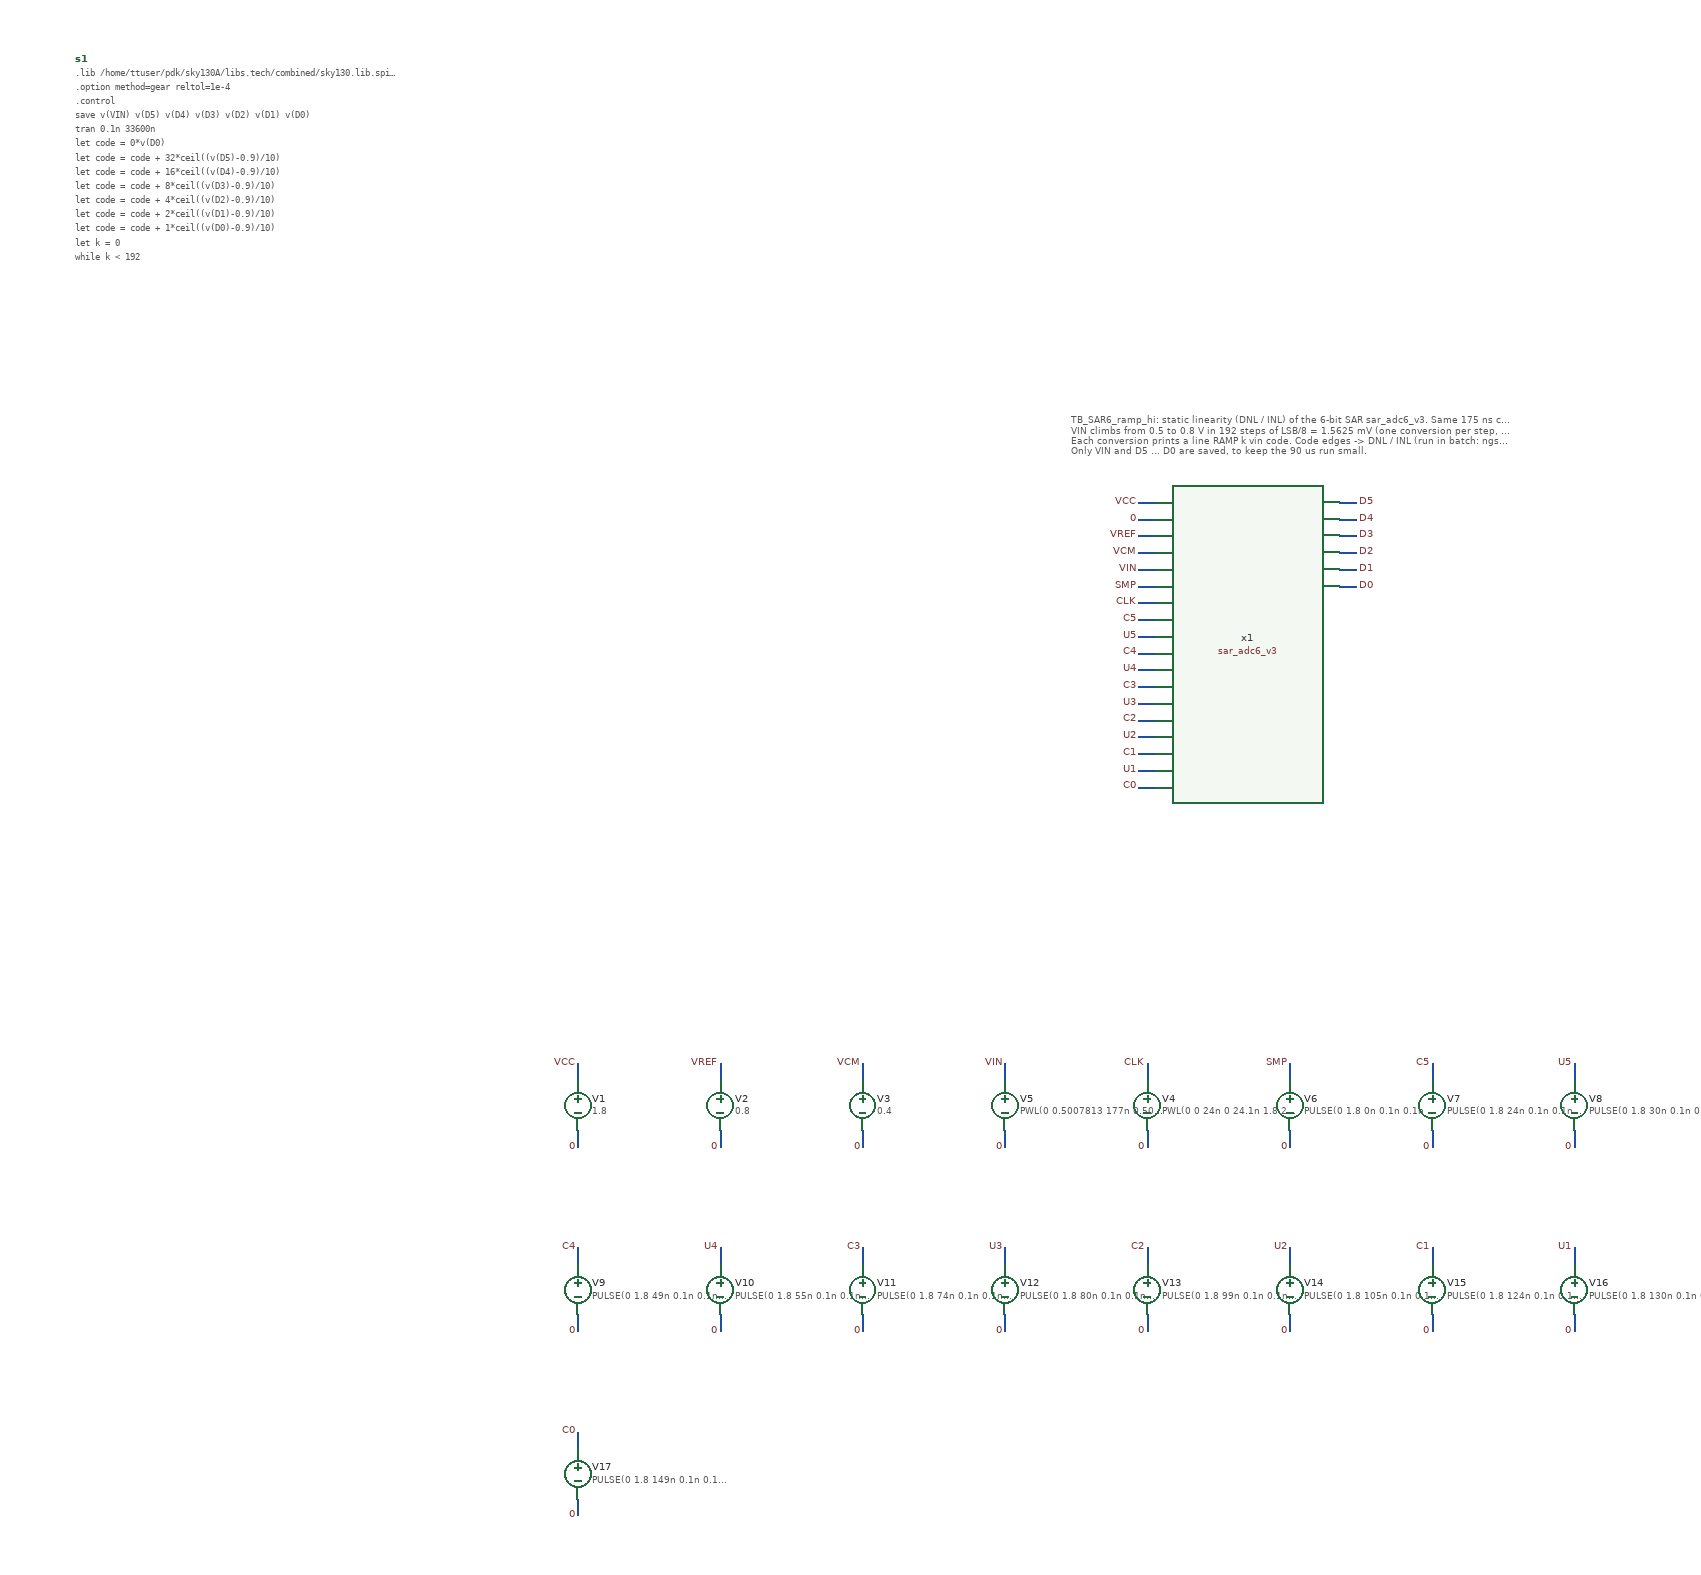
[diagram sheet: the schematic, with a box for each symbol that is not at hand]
v {xschem version=3.4.5 file_version=1.2
}
G {}
K {}
V {}
S {}
E {}
T {TB_SAR6_ramp_hi: static linearity (DNL / INL) of the 6-bit SAR sar_adc6_v3.  Same 175 ns conversion timing as TB_SAR6_v3.
VIN climbs from 0.5 to 0.8 V in 192 steps of LSB/8 = 1.5625 mV (one conversion per step, VIN changes 2 ns into SMP).
Each conversion prints a line  RAMP k vin code.  Code edges -> DNL / INL (run in batch:  ngspice -b TB_SAR6_ramp.spice > ramp_log.txt).
Only VIN and D5 ... D0 are saved, to keep the 90 us run small.} 290 -630 0 0 0.3 0.3 {}
C {/home/ttuser/Documents/ADCAnalogDesign/SAR_improved/sar_adc6_v3.sym} 500 -350 0 0 {name=x1}
N 390 -520 370 -520 {}
C {lab_pin.sym} 370 -520 0 0 {name=l1 sig_type=std_logic lab=VCC}
N 390 -500 370 -500 {}
C {lab_pin.sym} 370 -500 0 0 {name=l2 sig_type=std_logic lab=0}
N 390 -480 370 -480 {}
C {lab_pin.sym} 370 -480 0 0 {name=l3 sig_type=std_logic lab=VREF}
N 390 -460 370 -460 {}
C {lab_pin.sym} 370 -460 0 0 {name=l4 sig_type=std_logic lab=VCM}
N 390 -440 370 -440 {}
C {lab_pin.sym} 370 -440 0 0 {name=l5 sig_type=std_logic lab=VIN}
N 390 -420 370 -420 {}
C {lab_pin.sym} 370 -420 0 0 {name=l6 sig_type=std_logic lab=SMP}
N 390 -400 370 -400 {}
C {lab_pin.sym} 370 -400 0 0 {name=l7 sig_type=std_logic lab=CLK}
N 390 -380 370 -380 {}
C {lab_pin.sym} 370 -380 0 0 {name=l8 sig_type=std_logic lab=C5}
N 390 -360 370 -360 {}
C {lab_pin.sym} 370 -360 0 0 {name=l9 sig_type=std_logic lab=U5}
N 390 -340 370 -340 {}
C {lab_pin.sym} 370 -340 0 0 {name=l10 sig_type=std_logic lab=C4}
N 390 -320 370 -320 {}
C {lab_pin.sym} 370 -320 0 0 {name=l11 sig_type=std_logic lab=U4}
N 390 -300 370 -300 {}
C {lab_pin.sym} 370 -300 0 0 {name=l12 sig_type=std_logic lab=C3}
N 390 -280 370 -280 {}
C {lab_pin.sym} 370 -280 0 0 {name=l13 sig_type=std_logic lab=U3}
N 390 -260 370 -260 {}
C {lab_pin.sym} 370 -260 0 0 {name=l14 sig_type=std_logic lab=C2}
N 390 -240 370 -240 {}
C {lab_pin.sym} 370 -240 0 0 {name=l15 sig_type=std_logic lab=U2}
N 390 -220 370 -220 {}
C {lab_pin.sym} 370 -220 0 0 {name=l16 sig_type=std_logic lab=C1}
N 390 -200 370 -200 {}
C {lab_pin.sym} 370 -200 0 0 {name=l17 sig_type=std_logic lab=U1}
N 390 -180 370 -180 {}
C {lab_pin.sym} 370 -180 0 0 {name=l18 sig_type=std_logic lab=C0}
N 610 -520 630 -520 {}
C {lab_pin.sym} 630 -520 0 1 {name=l19 sig_type=std_logic lab=D5}
N 610 -500 630 -500 {}
C {lab_pin.sym} 630 -500 0 1 {name=l20 sig_type=std_logic lab=D4}
N 610 -480 630 -480 {}
C {lab_pin.sym} 630 -480 0 1 {name=l21 sig_type=std_logic lab=D3}
N 610 -460 630 -460 {}
C {lab_pin.sym} 630 -460 0 1 {name=l22 sig_type=std_logic lab=D2}
N 610 -440 630 -440 {}
C {lab_pin.sym} 630 -440 0 1 {name=l23 sig_type=std_logic lab=D1}
N 610 -420 630 -420 {}
C {lab_pin.sym} 630 -420 0 1 {name=l24 sig_type=std_logic lab=D0}
C {vsource.sym} -300 200 0 0 {name=V1 value="1.8" savecurrent=false}
N -300 170 -300 150 {}
C {lab_pin.sym} -300 150 0 0 {name=l25 sig_type=std_logic lab=VCC}
N -300 230 -300 250 {}
C {lab_pin.sym} -300 250 0 0 {name=l26 sig_type=std_logic lab=0}
C {vsource.sym} -130 200 0 0 {name=V2 value="0.8" savecurrent=false}
N -130 170 -130 150 {}
C {lab_pin.sym} -130 150 0 0 {name=l27 sig_type=std_logic lab=VREF}
N -130 230 -130 250 {}
C {lab_pin.sym} -130 250 0 0 {name=l28 sig_type=std_logic lab=0}
C {vsource.sym} 40 200 0 0 {name=V3 value="0.4" savecurrent=false}
N 40 170 40 150 {}
C {lab_pin.sym} 40 150 0 0 {name=l29 sig_type=std_logic lab=VCM}
N 40 230 40 250 {}
C {lab_pin.sym} 40 250 0 0 {name=l30 sig_type=std_logic lab=0}
C {vsource.sym} 210 200 0 0 {name=V5 value="PWL(0 0.5007813 177n 0.5007813 177.5n 0.5023437 352n 0.5023437 352.5n 0.5039062 527n 0.5039062 527.5n 0.5054688 702n 0.5054688 702.5n 0.5070313 877n 0.5070313 877.5n 0.5085938 1052n 0.5085938 1052.5n 0.5101562 1227n 0.5101562 1227.5n 0.5117188 1402n 0.5117188 1402.5n 0.5132813 1577n 0.5132813 1577.5n 0.5148438 1752n 0.5148438 1752.5n 0.5164063 1927n 0.5164063 1927.5n 0.5179687 2102n 0.5179687 2102.5n 0.5195312 2277n 0.5195312 2277.5n 0.5210938 2452n 0.5210938 2452.5n 0.5226563 2627n 0.5226563 2627.5n 0.5242188 2802n 0.5242188 2802.5n 0.5257812 2977n 0.5257812 2977.5n 0.5273438 3152n 0.5273438 3152.5n 0.5289063 3327n 0.5289063 3327.5n 0.5304688 3502n 0.5304688 3502.5n 0.5320313 3677n 0.5320313 3677.5n 0.5335937 3852n 0.5335937 3852.5n 0.5351562 4027n 0.5351562 4027.5n 0.5367188 4202n 0.5367188 4202.5n 0.5382813 4377n 0.5382813 4377.5n 0.5398438 4552n 0.5398438 4552.5n 0.5414062 4727n 0.5414062 4727.5n 0.5429688 4902n 0.5429688 4902.5n 0.5445313 5077n 0.5445313 5077.5n 0.5460938 5252n 0.5460938 5252.5n 0.5476563 5427n 0.5476563 5427.5n 0.5492187 5602n 0.5492187 5602.5n 0.5507812 5777n 0.5507812 5777.5n 0.5523438 5952n 0.5523438 5952.5n 0.5539063 6127n 0.5539063 6127.5n 0.5554688 6302n 0.5554688 6302.5n 0.5570312 6477n 0.5570312 6477.5n 0.5585938 6652n 0.5585938 6652.5n 0.5601563 6827n 0.5601563 6827.5n 0.5617188 7002n 0.5617188 7002.5n 0.5632813 7177n 0.5632813 7177.5n 0.5648437 7352n 0.5648437 7352.5n 0.5664062 7527n 0.5664062 7527.5n 0.5679688 7702n 0.5679688 7702.5n 0.5695313 7877n 0.5695313 7877.5n 0.5710938 8052n 0.5710938 8052.5n 0.5726562 8227n 0.5726562 8227.5n 0.5742188 8402n 0.5742188 8402.5n 0.5757813 8577n 0.5757813 8577.5n 0.5773438 8752n 0.5773438 8752.5n 0.5789063 8927n 0.5789063 8927.5n 0.5804687 9102n 0.5804687 9102.5n 0.5820312 9277n 0.5820312 9277.5n 0.5835938 9452n 0.5835938 9452.5n 0.5851563 9627n 0.5851563 9627.5n 0.5867188 9802n 0.5867188 9802.5n 0.5882812 9977n 0.5882812 9977.5n 0.5898438 10152n 0.5898438 10152.5n 0.5914063 10327n 0.5914063 10327.5n 0.5929688 10502n 0.5929688 10502.5n 0.5945313 10677n 0.5945313 10677.5n 0.5960937 10852n 0.5960937 10852.5n 0.5976562 11027n 0.5976562 11027.5n 0.5992188 11202n 0.5992188 11202.5n 0.6007813 11377n 0.6007813 11377.5n 0.6023438 11552n 0.6023438 11552.5n 0.6039063 11727n 0.6039063 11727.5n 0.6054688 11902n 0.6054688 11902.5n 0.6070313 12077n 0.6070313 12077.5n 0.6085938 12252n 0.6085938 12252.5n 0.6101563 12427n 0.6101563 12427.5n 0.6117188 12602n 0.6117188 12602.5n 0.6132812 12777n 0.6132812 12777.5n 0.6148438 12952n 0.6148438 12952.5n 0.6164063 13127n 0.6164063 13127.5n 0.6179688 13302n 0.6179688 13302.5n 0.6195313 13477n 0.6195313 13477.5n 0.6210938 13652n 0.6210938 13652.5n 0.6226563 13827n 0.6226563 13827.5n 0.6242188 14002n 0.6242188 14002.5n 0.6257813 14177n 0.6257813 14177.5n 0.6273438 14352n 0.6273438 14352.5n 0.6289062 14527n 0.6289062 14527.5n 0.6304688 14702n 0.6304688 14702.5n 0.6320313 14877n 0.6320313 14877.5n 0.6335938 15052n 0.6335938 15052.5n 0.6351563 15227n 0.6351563 15227.5n 0.6367188 15402n 0.6367188 15402.5n 0.6382813 15577n 0.6382813 15577.5n 0.6398438 15752n 0.6398438 15752.5n 0.6414063 15927n 0.6414063 15927.5n 0.6429688 16102n 0.6429688 16102.5n 0.6445312 16277n 0.6445312 16277.5n 0.6460938 16452n 0.6460938 16452.5n 0.6476563 16627n 0.6476563 16627.5n 0.6492188 16802n 0.6492188 16802.5n 0.6507813 16977n 0.6507813 16977.5n 0.6523438 17152n 0.6523438 17152.5n 0.6539063 17327n 0.6539063 17327.5n 0.6554688 17502n 0.6554688 17502.5n 0.6570313 17677n 0.6570313 17677.5n 0.6585938 17852n 0.6585938 17852.5n 0.6601562 18027n 0.6601562 18027.5n 0.6617188 18202n 0.6617188 18202.5n 0.6632813 18377n 0.6632813 18377.5n 0.6648438 18552n 0.6648438 18552.5n 0.6664063 18727n 0.6664063 18727.5n 0.6679688 18902n 0.6679688 18902.5n 0.6695313 19077n 0.6695313 19077.5n 0.6710938 19252n 0.6710938 19252.5n 0.6726563 19427n 0.6726563 19427.5n 0.6742188 19602n 0.6742188 19602.5n 0.6757812 19777n 0.6757812 19777.5n 0.6773438 19952n 0.6773438 19952.5n 0.6789063 20127n 0.6789063 20127.5n 0.6804688 20302n 0.6804688 20302.5n 0.6820313 20477n 0.6820313 20477.5n 0.6835938 20652n 0.6835938 20652.5n 0.6851563 20827n 0.6851563 20827.5n 0.6867188 21002n 0.6867188 21002.5n 0.6882813 21177n 0.6882813 21177.5n 0.6898438 21352n 0.6898438 21352.5n 0.6914062 21527n 0.6914062 21527.5n 0.6929688 21702n 0.6929688 21702.5n 0.6945313 21877n 0.6945313 21877.5n 0.6960938 22052n 0.6960938 22052.5n 0.6976563 22227n 0.6976563 22227.5n 0.6992188 22402n 0.6992188 22402.5n 0.7007813 22577n 0.7007813 22577.5n 0.7023438 22752n 0.7023438 22752.5n 0.7039063 22927n 0.7039063 22927.5n 0.7054688 23102n 0.7054688 23102.5n 0.7070312 23277n 0.7070312 23277.5n 0.7085938 23452n 0.7085938 23452.5n 0.7101563 23627n 0.7101563 23627.5n 0.7117188 23802n 0.7117188 23802.5n 0.7132813 23977n 0.7132813 23977.5n 0.7148438 24152n 0.7148438 24152.5n 0.7164063 24327n 0.7164063 24327.5n 0.7179688 24502n 0.7179688 24502.5n 0.7195313 24677n 0.7195313 24677.5n 0.7210938 24852n 0.7210938 24852.5n 0.7226562 25027n 0.7226562 25027.5n 0.7242188 25202n 0.7242188 25202.5n 0.7257813 25377n 0.7257813 25377.5n 0.7273438 25552n 0.7273438 25552.5n 0.7289063 25727n 0.7289063 25727.5n 0.7304688 25902n 0.7304688 25902.5n 0.7320313 26077n 0.7320313 26077.5n 0.7335938 26252n 0.7335938 26252.5n 0.7351563 26427n 0.7351563 26427.5n 0.7367188 26602n 0.7367188 26602.5n 0.7382812 26777n 0.7382812 26777.5n 0.7398438 26952n 0.7398438 26952.5n 0.7414063 27127n 0.7414063 27127.5n 0.7429688 27302n 0.7429688 27302.5n 0.7445313 27477n 0.7445313 27477.5n 0.7460938 27652n 0.7460938 27652.5n 0.7476563 27827n 0.7476563 27827.5n 0.7492188 28002n 0.7492188 28002.5n 0.7507813 28177n 0.7507813 28177.5n 0.7523438 28352n 0.7523438 28352.5n 0.7539062 28527n 0.7539062 28527.5n 0.7554688 28702n 0.7554688 28702.5n 0.7570313 28877n 0.7570313 28877.5n 0.7585938 29052n 0.7585938 29052.5n 0.7601563 29227n 0.7601563 29227.5n 0.7617188 29402n 0.7617188 29402.5n 0.7632813 29577n 0.7632813 29577.5n 0.7648438 29752n 0.7648438 29752.5n 0.7664063 29927n 0.7664063 29927.5n 0.7679688 30102n 0.7679688 30102.5n 0.7695312 30277n 0.7695312 30277.5n 0.7710938 30452n 0.7710938 30452.5n 0.7726563 30627n 0.7726563 30627.5n 0.7742188 30802n 0.7742188 30802.5n 0.7757813 30977n 0.7757813 30977.5n 0.7773438 31152n 0.7773438 31152.5n 0.7789063 31327n 0.7789063 31327.5n 0.7804688 31502n 0.7804688 31502.5n 0.7820313 31677n 0.7820313 31677.5n 0.7835938 31852n 0.7835938 31852.5n 0.7851562 32027n 0.7851562 32027.5n 0.7867188 32202n 0.7867188 32202.5n 0.7882813 32377n 0.7882813 32377.5n 0.7898438 32552n 0.7898438 32552.5n 0.7914063 32727n 0.7914063 32727.5n 0.7929688 32902n 0.7929688 32902.5n 0.7945313 33077n 0.7945313 33077.5n 0.7960938 33252n 0.7960938 33252.5n 0.7976563 33427n 0.7976563 33427.5n 0.7992188)" savecurrent=false}
N 210 170 210 150 {}
C {lab_pin.sym} 210 150 0 0 {name=l31 sig_type=std_logic lab=VIN}
N 210 230 210 250 {}
C {lab_pin.sym} 210 250 0 0 {name=l32 sig_type=std_logic lab=0}
C {vsource.sym} 380 200 0 0 {name=V4 value="PWL(0 0 24n 0 24.1n 1.8 28n 1.8 28.1n 0 49n 0 49.1n 1.8 53n 1.8 53.1n 0 74n 0 74.1n 1.8 78n 1.8 78.1n 0 99n 0 99.1n 1.8 103n 1.8 103.1n 0 124n 0 124.1n 1.8 128n 1.8 128.1n 0 149n 0 149.1n 1.8 153n 1.8 153.1n 0 175n 0) r=0" savecurrent=false}
N 380 170 380 150 {}
C {lab_pin.sym} 380 150 0 0 {name=l33 sig_type=std_logic lab=CLK}
N 380 230 380 250 {}
C {lab_pin.sym} 380 250 0 0 {name=l34 sig_type=std_logic lab=0}
C {vsource.sym} 550 200 0 0 {name=V6 value="PULSE(0 1.8 0n 0.1n 0.1n 19.9n 175n)" savecurrent=false}
N 550 170 550 150 {}
C {lab_pin.sym} 550 150 0 0 {name=l35 sig_type=std_logic lab=SMP}
N 550 230 550 250 {}
C {lab_pin.sym} 550 250 0 0 {name=l36 sig_type=std_logic lab=0}
C {vsource.sym} 720 200 0 0 {name=V7 value="PULSE(0 1.8 24n 0.1n 0.1n 3.9n 175n)" savecurrent=false}
N 720 170 720 150 {}
C {lab_pin.sym} 720 150 0 0 {name=l37 sig_type=std_logic lab=C5}
N 720 230 720 250 {}
C {lab_pin.sym} 720 250 0 0 {name=l38 sig_type=std_logic lab=0}
C {vsource.sym} 890 200 0 0 {name=V8 value="PULSE(0 1.8 30n 0.1n 0.1n 4.9n 175n)" savecurrent=false}
N 890 170 890 150 {}
C {lab_pin.sym} 890 150 0 0 {name=l39 sig_type=std_logic lab=U5}
N 890 230 890 250 {}
C {lab_pin.sym} 890 250 0 0 {name=l40 sig_type=std_logic lab=0}
C {vsource.sym} -300 420 0 0 {name=V9 value="PULSE(0 1.8 49n 0.1n 0.1n 3.9n 175n)" savecurrent=false}
N -300 390 -300 370 {}
C {lab_pin.sym} -300 370 0 0 {name=l41 sig_type=std_logic lab=C4}
N -300 450 -300 470 {}
C {lab_pin.sym} -300 470 0 0 {name=l42 sig_type=std_logic lab=0}
C {vsource.sym} -130 420 0 0 {name=V10 value="PULSE(0 1.8 55n 0.1n 0.1n 4.9n 175n)" savecurrent=false}
N -130 390 -130 370 {}
C {lab_pin.sym} -130 370 0 0 {name=l43 sig_type=std_logic lab=U4}
N -130 450 -130 470 {}
C {lab_pin.sym} -130 470 0 0 {name=l44 sig_type=std_logic lab=0}
C {vsource.sym} 40 420 0 0 {name=V11 value="PULSE(0 1.8 74n 0.1n 0.1n 3.9n 175n)" savecurrent=false}
N 40 390 40 370 {}
C {lab_pin.sym} 40 370 0 0 {name=l45 sig_type=std_logic lab=C3}
N 40 450 40 470 {}
C {lab_pin.sym} 40 470 0 0 {name=l46 sig_type=std_logic lab=0}
C {vsource.sym} 210 420 0 0 {name=V12 value="PULSE(0 1.8 80n 0.1n 0.1n 4.9n 175n)" savecurrent=false}
N 210 390 210 370 {}
C {lab_pin.sym} 210 370 0 0 {name=l47 sig_type=std_logic lab=U3}
N 210 450 210 470 {}
C {lab_pin.sym} 210 470 0 0 {name=l48 sig_type=std_logic lab=0}
C {vsource.sym} 380 420 0 0 {name=V13 value="PULSE(0 1.8 99n 0.1n 0.1n 3.9n 175n)" savecurrent=false}
N 380 390 380 370 {}
C {lab_pin.sym} 380 370 0 0 {name=l49 sig_type=std_logic lab=C2}
N 380 450 380 470 {}
C {lab_pin.sym} 380 470 0 0 {name=l50 sig_type=std_logic lab=0}
C {vsource.sym} 550 420 0 0 {name=V14 value="PULSE(0 1.8 105n 0.1n 0.1n 4.9n 175n)" savecurrent=false}
N 550 390 550 370 {}
C {lab_pin.sym} 550 370 0 0 {name=l51 sig_type=std_logic lab=U2}
N 550 450 550 470 {}
C {lab_pin.sym} 550 470 0 0 {name=l52 sig_type=std_logic lab=0}
C {vsource.sym} 720 420 0 0 {name=V15 value="PULSE(0 1.8 124n 0.1n 0.1n 3.9n 175n)" savecurrent=false}
N 720 390 720 370 {}
C {lab_pin.sym} 720 370 0 0 {name=l53 sig_type=std_logic lab=C1}
N 720 450 720 470 {}
C {lab_pin.sym} 720 470 0 0 {name=l54 sig_type=std_logic lab=0}
C {vsource.sym} 890 420 0 0 {name=V16 value="PULSE(0 1.8 130n 0.1n 0.1n 4.9n 175n)" savecurrent=false}
N 890 390 890 370 {}
C {lab_pin.sym} 890 370 0 0 {name=l55 sig_type=std_logic lab=U1}
N 890 450 890 470 {}
C {lab_pin.sym} 890 470 0 0 {name=l56 sig_type=std_logic lab=0}
C {vsource.sym} -300 640 0 0 {name=V17 value="PULSE(0 1.8 149n 0.1n 0.1n 3.9n 175n)" savecurrent=false}
N -300 610 -300 590 {}
C {lab_pin.sym} -300 590 0 0 {name=l57 sig_type=std_logic lab=C0}
N -300 670 -300 690 {}
C {lab_pin.sym} -300 690 0 0 {name=l58 sig_type=std_logic lab=0}
C {code_shown.sym} -900 -1050 0 0 {name=s1 only_toplevel=false value=".lib /home/ttuser/pdk/sky130A/libs.tech/combined/sky130.lib.spice tt
.option method=gear reltol=1e-4
.control
save v(VIN) v(D5) v(D4) v(D3) v(D2) v(D1) v(D0)
tran 0.1n 33600n
let code = 0*v(D0)
let code = code + 32*ceil((v(D5)-0.9)/10)
let code = code + 16*ceil((v(D4)-0.9)/10)
let code = code + 8*ceil((v(D3)-0.9)/10)
let code = code + 4*ceil((v(D2)-0.9)/10)
let code = code + 2*ceil((v(D1)-0.9)/10)
let code = code + 1*ceil((v(D0)-0.9)/10)
let k = 0
while k < 192
  let tr = k*175e-9 + 165e-9
  meas tran ck find code at=$&tr
  meas tran vk find v(VIN) at=$&tr
  echo RAMP $&k $&vk $&ck
  let k = k + 1
end
plot code
.endc"}
